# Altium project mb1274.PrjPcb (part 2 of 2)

## Sheet 05_USB_OTG_FS.SchDoc: USB_OTG_FS
size A4; Date: 04/02/2015; Author: P.A.; CompanyName: STMicroelectronics; Organization: Microcontrollers Division; Address1: 12, Rue Jules HOROWITZ; Address2: 38019 Grenoble; Address3: FRANCE; DocumentNumber: 8; Revision: E-01; SheetNumber: 8; SheetTotal: 12; Project: STM32F413H-DISCO

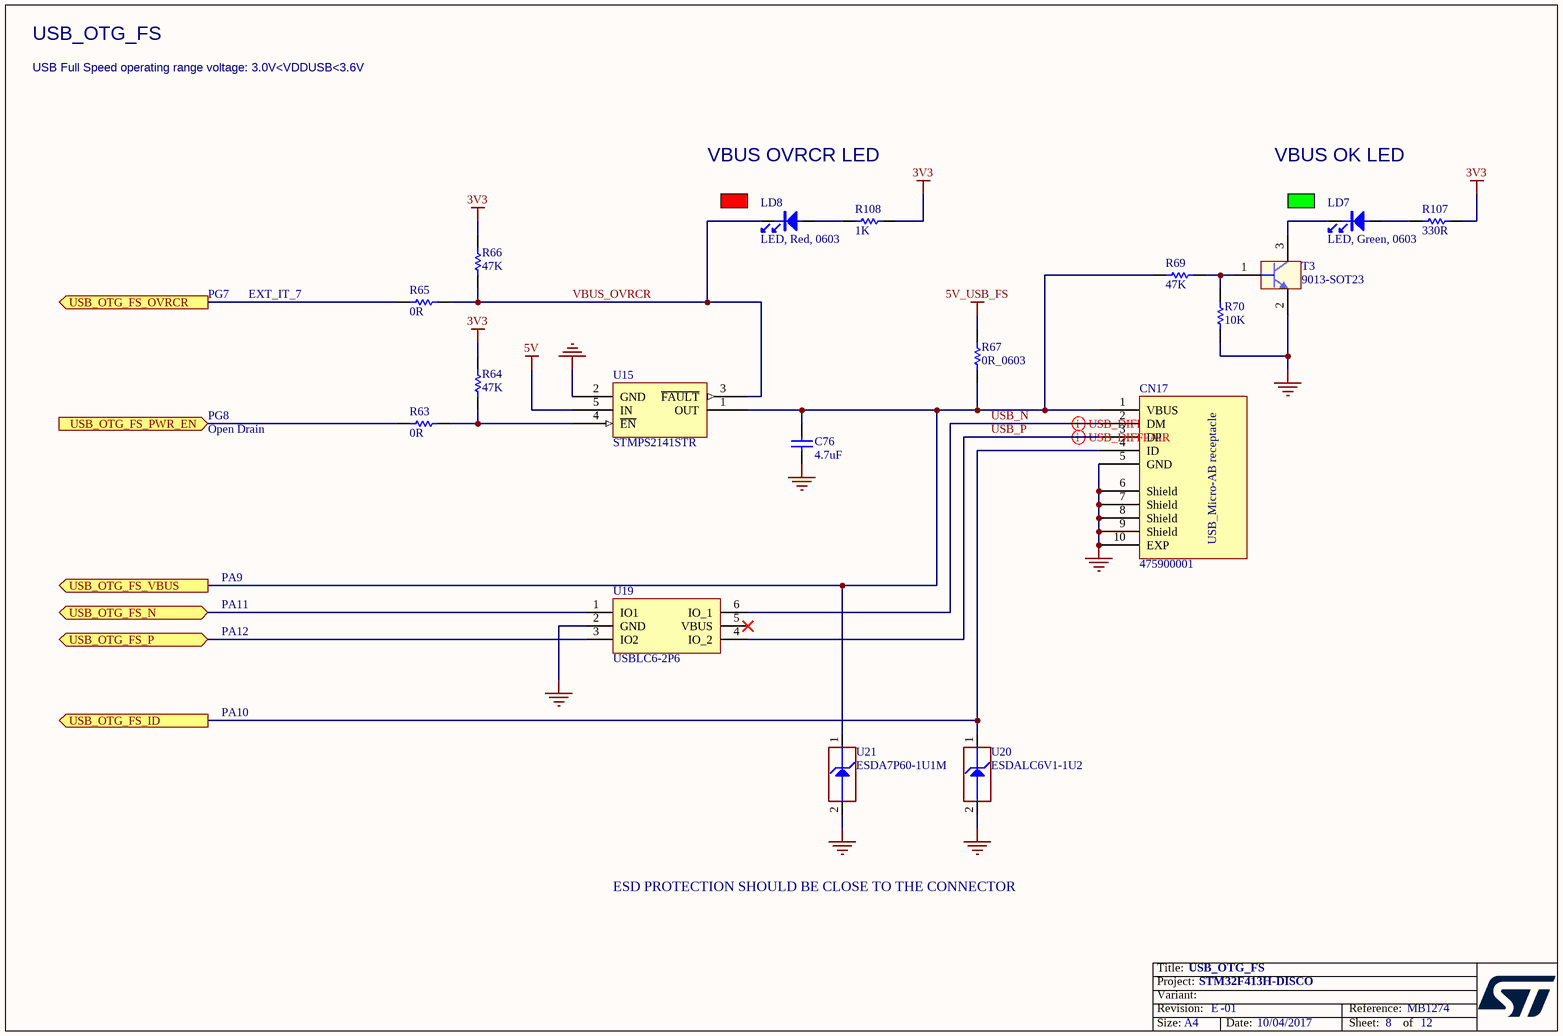
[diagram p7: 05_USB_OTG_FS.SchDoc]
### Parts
C76  4.7uF  [C0603]
CN17  475900001  [CON_USBMICROAB_MOLEX_47590-0001_H3]
LD7  LED, Green, 0603  [LED_0603_GREEN]
LD8  LED, Red, 0603  [LED_0603_RED]
R63  0R  [R0402]
R64  47K  [R0402]
R65  0R  [R0402]
R66  47K  [R0402]
R67  0R_0603  [R0603]
R69  47K  [R0402]
R70  10K  [R0402]
R107  330R  [R0402]
R108  1K  [R0402]
T3  9013-SOT23  [NPN_SOT23]
U15  STMPS2141STR  [MOS_SOT23-5L]
U19  USBLC6-2P6  [ESD_SOT666]
U20  ESDALC6V1-1U2  [ESD_ST0201]
U21  ESDA7P60-1U1M  [ESD_QFN2_1P6X1_P125]

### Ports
USB_OTG_FS_ID (out), USB_OTG_FS_N (bidir), USB_OTG_FS_OVRCR (out), USB_OTG_FS_P (bidir), USB_OTG_FS_PWR_EN (in), USB_OTG_FS_VBUS (out)

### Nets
3V3: R64.2 R66.2 R107.2 R108.1
5V: U15.5(IN)
5V_USB_FS: R67.2
GND: C76.1 CN17.5(GND) CN17.6(Shield) CN17.7(Shield) CN17.8(Shield) CN17.9(Shield) CN17.10(EXP) R70.1 T3.2(E) U15.2(GND) U19.2(GND) U20.2(GND) U21.2(GND)
USB_N: CN17.2(DM) U19.6(IO_1)
USB_OTG_FS_ID: CN17.4(ID) U20.1(IO1) ; port USB_OTG_FS_ID
USB_OTG_FS_N: U19.1(IO1) ; port USB_OTG_FS_N
USB_OTG_FS_OVRCR: R65.1 ; port USB_OTG_FS_OVRCR
USB_OTG_FS_P: U19.3(IO2) ; port USB_OTG_FS_P
USB_OTG_FS_PWR_EN: R63.1 ; port USB_OTG_FS_PWR_EN
USB_OTG_FS_VBUS: C76.2 CN17.1(VBUS) R67.1 R69.1 U15.1(OUT) U21.1(IO1) ; port USB_OTG_FS_VBUS
USB_P: CN17.3(DP) U19.4(IO_2)
VBUS_OVRCR: LD8.2 R65.2 R66.1 U15.3(~{FAULT})
NetLD7_1: LD7.1 R107.1
NetLD7_2: LD7.2 T3.3(C)
NetLD8_1: LD8.1 R108.2
NetR63_2: R63.2 R64.1 U15.4(~{EN})
NetR69_2: R69.2 R70.2 T3.1(B)

Not connected (* = marked no-connect by the designer): U19 5(VBUS)*

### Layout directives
differential pair; rule Matched Net Lengths [Tolerance = 0.5mm]; rule Impedance Constraint [Min = 85.00    Max = 95.00    ]: USB_N, USB_P

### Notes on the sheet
- USB_OTG_FS
- USB Full Speed operating range voltage: 3.0V<VDDUSB<3.6V
- VBUS OVRCR LED
- VBUS OK LED
- PG7
- EXT_IT_7
- Open Drain
- PG8
- PA9
- PA11
- PA12
- PA10
- ESD PROTECTION SHOULD BE CLOSE TO THE CONNECTOR

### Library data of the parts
C76 = Cap_4.7uF_X5R_10%_0603: Capacitor,4.7uF,16V, X5R,10%,0603,YAGEO; Manuf_Part_1: CC0603KRX5R7BB475; Fitted: YES; Order_Code: CC0603KRX5R7BB105; Ordered_By: subcon
CN17 = 475900001: USB-MICRO-AB, 47590-0001, SMT, MOLEX; Fitted: YES; Ordered_By: Subcon
LD7 = LED_green: Manuf_1: everlight; Manuf_Part_1: 19-213SYGC/S530-E2/TR8; ECCN_US/EU: EAR99/NEC; Fitted: YES; Ordered_By: Subcon
LD8 = LED_red: Manuf_1: everlight; Manuf_Part_1: 19-213-R6C-AP1Q2B/3T; ECCN_US/EU: EAR99/NEC; Fitted: YES; Ordered_By: Subcon
R63 R65 = Res_0_5%_0402: Resistor,0R,0402,5%,YAGEO; Manuf_Part_1: RC0402JR-070RL; Fitted: YES; Order_Code: 2363467; Ordered_By: Subcon
R64 R66 R69 = Res_47K_1%_0402: Resistor,47K,0402,1%,YAGEO; Manuf_Part_1: RC0402FR-0747KL; Fitted: YES; Order_Code: 9239430; Ordered_By: Subcon
R67 = Res_0_5%_0603: Resistor,0R,0603,5%,YAGEO; Manuf_Part_1: RC0603JR-070RL; Fitted: YES; Order_Code: 2363481; Ordered_By: subcon
R70 = Res_10K_1%_0402: Resistor,10K,0402,1%,YAGEO; Manuf_Part_1: RC0402FR-0710KL; Fitted: YES; Ordered_By: subcon
R107 = Res_330_1%_0402: Resistor,330R,0402,1%,YAGEO; Manuf_Part_1: RC0402FR-07330RL; Fitted: YES; Ordered_By: Subcon
R108 = Res_1K_1%_0402: Resistor,1K,0402,1%,YAGEO; Manuf_Part_1: RC0402FR-071KL; Fitted: YES; Ordered_By: Subcon
T3 = 9013-SOT23: NPN Bipolar Transistor; Manuf_1: NXP; Manuf_Part_1: BSR14; ECCN_US/EU: EAR99/NEC; Fitted: YES; Order_Code: 1081310; Ordered_By: Subcon
U15 = STMPS2141STR: Enhanced single channel power switches; Manuf_1: STM; ECCN_US/EU: EAR99/NEC; Ref St: 9159003; Fitted: YES
U19 = USBLC6-2P6: USB ESD protection; Ordered_By: STM; ECCN_US/EU: EAR99; Fitted: YES
U20 = ESDALC6V1-1U2: Dual Transil array for ESD protection; Manuf_1: STM; Ref St: .; ECCN_US/EU: EAR99/NEC; Fitted: YES; Provided: ST
U21 = MCD-00251: High power transient voltage suppressor, 7V breakdown; Manuf_1: STM; ECCN_US/EU: EAR99/NEC; Fitted: YES

## Sheet 06_Peripherals.SchDoc: Peripherals
size A4; Date: 9/24/2014; Author: P.A.; CompanyName: STMicroelectronics; Organization: Microcontrollers Division; Address1: 12, Rue Jules HOROWITZ; Address2: 38019 Grenoble; Address3: FRANCE; DocumentNumber: 9; Revision: E-01; SheetNumber: 9; SheetTotal: 12; Project: STM32F413H-DISCO

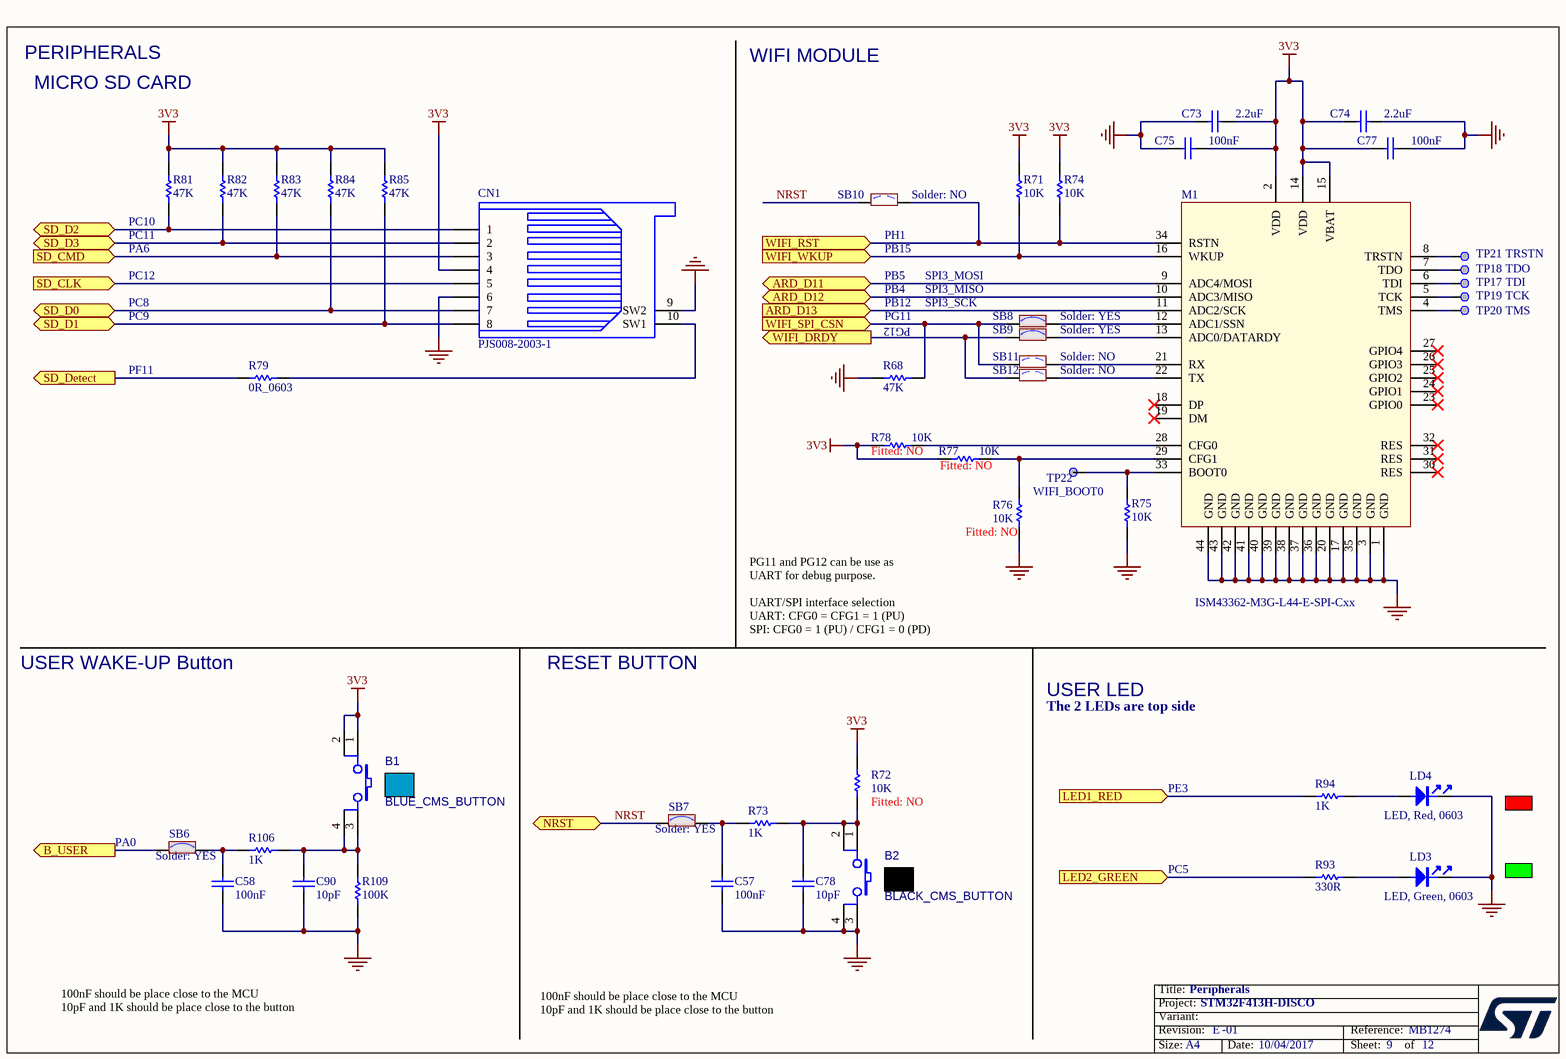
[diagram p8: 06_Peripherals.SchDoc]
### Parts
B1  BLUE_CMS_BUTTON  [SWI_C&K_KSC721GLFS_BLUE]
B2  BLACK_CMS_BUTTON  [SWI_C&K_KSC321GLFS_BLACK]
C57  100nF  [C0402]
C58  100nF  [C0402]
C73  2.2uF  [C0603]
C74  2.2uF  [C0603]
C75  100nF  [C0402]
C77  100nF  [C0402]
C78  10pF  [C0402]
C90  10pF  [C0402]
CN1  PJS008-2003-1  [CON_MICROSD_YAMAICHI_PJS008-2003-1]
LD3  LED, Green, 0603  [LED_0603_GREEN]
LD4  LED, Red, 0603  [LED_0603_RED]
M1  ISM43362-M3G-L44-E-SPI-Cxx  [MOD_WIFI_INVENTEK-SYSTEMS_ISM43362-M3G-L44-E-SPI-CXX]
R68  47K  [R0402]
R71  10K  [R0402]
R72  10K  Fitted: NO  [R0402]
R73  1K  [R0402]
R74  10K  [R0402]
R75  10K  [R0402]
R76  10K  Fitted: NO  [R0402]
R77  10K  Fitted: NO  [R0402]
R78  10K  Fitted: NO  [R0402]
R79  0R_0603  [R0603]
R81  47K  [R0402]
R82  47K  [R0402]
R83  47K  [R0402]
R84  47K  [R0402]
R85  47K  [R0402]
R93  330R  [R0402]
R94  1K  [R0402]
R106  1K  [R0402]
R109  100K  [R0402]
SB6  Solder: YES  [SOLDER-BRIDGE_R0603-0R]  (hidden comment: SB_ON)
SB7  Solder: YES  [SOLDER-BRIDGE_R0603-0R]  (hidden comment: SB_ON)
SB8  Solder: YES  [SOLDER-BRIDGE_R0603-0R]  (hidden comment: SB_ON)
SB9  Solder: YES  [SOLDER-BRIDGE_R0603-0R]  (hidden comment: SB_ON)
SB10  Solder: NO  [SOLDER-BRIDGE_R0603-0R]  (hidden comment: SB_OFF)
SB11  Solder: NO  [SOLDER-BRIDGE_R0603-0R]  (hidden comment: SB_OFF)
SB12  Solder: NO  [SOLDER-BRIDGE_R0603-0R]  (hidden comment: SB_OFF)
TP17  TDI  [TP_SMD_2MM]
TP18  TDO  [TP_SMD_2MM]
TP19  TCK  [TP_SMD_2MM]
TP20  TMS  [TP_SMD_2MM]
TP21  TRSTN  [TP_SMD_2MM]
TP22  WIFI_BOOT0  [TP_SMD_1MM]

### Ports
ARD_D11 (bidir), ARD_D12 (bidir), ARD_D13 (in), B_USER (out), LED1_RED (in), LED2_GREEN (in), NRST (bidir), SD_CLK (in), SD_CMD (in), SD_D0 (bidir), SD_D1 (bidir), SD_D2 (bidir), SD_D3 (bidir), SD_Detect (out), WIFI_DRDY (out), WIFI_RST (in), WIFI_SPI_CSN (in), WIFI_WKUP (in)

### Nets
3V3: B1.1 B1.2 C73.1 C74.1 C75.2 C77.1 CN1.4 M1.2(VDD) M1.14(VDD) M1.15(VBAT) R71.2 R72.2 R74.2 R77.1 R78.1 R81.2 R82.2 R83.2 R84.2 R85.2
GND: B2.3 B2.4 C57.1 C58.1 C73.2 C74.2 C75.1 C77.2 C78.1 C90.1 CN1.6 CN1.9(SW2) LD3.2 LD4.2 M1.1(GND) M1.3(GND) M1.17(GND) M1.20(GND) M1.35(GND) M1.36(GND) M1.37(GND) M1.38(GND) M1.39(GND) M1.40(GND) M1.41(GND) M1.42(GND) M1.43(GND) M1.44(GND) R68.1 R75.2 R76.2 R109.1
ARD_D11: M1.9(ADC4/MOSI) ; port ARD_D11
ARD_D12: M1.10(ADC3/MISO) ; port ARD_D12
ARD_D13: M1.11(ADC2/SCK) ; port ARD_D13
B_USER: SB6.1 ; port B_USER
LED1_RED: R94.2 ; port LED1_RED
LED2_GREEN: R93.1 ; port LED2_GREEN
NRST: SB7.1 SB10.1 ; port NRST
SD_CLK: CN1.5 ; port SD_CLK
SD_CMD: CN1.3 R83.1 ; port SD_CMD
SD_D0: CN1.7 R84.1 ; port SD_D0
SD_D1: CN1.8 R85.1 ; port SD_D1
SD_D2: CN1.1 R81.1 ; port SD_D2
SD_D3: CN1.2 R82.1 ; port SD_D3
SD_Detect: R79.1 ; port SD_Detect
WIFI_DRDY: SB9.1 SB12.1 ; port WIFI_DRDY
WIFI_RST: M1.34(RSTN) R74.1 SB10.2 ; port WIFI_RST
WIFI_SPI_CSN: R68.2 SB8.1 SB11.1 ; port WIFI_SPI_CSN
WIFI_WKUP: M1.16(WKUP) R71.1 ; port WIFI_WKUP
NetB1_3: B1.3 B1.4 C90.2 R106.2 R109.2
NetB2_1: B2.1 B2.2 C78.2 R72.1 R73.2
NetC57_2: C57.2 R73.1 SB7.2
NetC58_2: C58.2 R106.1 SB6.2
NetCN1_10: CN1.10(SW1) R79.2
NetLD3_1: LD3.1 R93.2
NetLD4_1: LD4.1 R94.1
NetM1_4: M1.4(TMS) TP20.1
NetM1_5: M1.5(TCK) TP19.1
NetM1_6: M1.6(TDI) TP17.1
NetM1_7: M1.7(TDO) TP18.1
NetM1_8: M1.8(TRSTN) TP21.1
NetM1_12: M1.12(ADC1/SSN) SB8.2
NetM1_13: M1.13(ADC0/DATARDY) SB9.2
NetM1_21: M1.21(RX) SB11.2
NetM1_22: M1.22(TX) SB12.2
NetM1_28: M1.28(CFG0) R78.2
NetM1_29: M1.29(CFG1) R76.1 R77.2
NetM1_33: M1.33(BOOT0) R75.1 TP22.1

Not connected (* = marked no-connect by the designer): M1 18(DP)* 19(DM)* 23(GPIO0)* 24(GPIO1)* 25(GPIO2)* 26(GPIO3)* 27(GPIO4)* 30(RES)* 31(RES)* 32(RES)*

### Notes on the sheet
- PERIPHERALS
- WIFI MODULE
- MICRO SD CARD
- (near R81) PC10
- (near R81) PC11
- (near R81) PA6
- (near SB10) PB15
- (near SB10) PH1
- PC12
- PC8
- PC9
- PG11
- PB5
- PB4
- PB12
- (near R68) PG12
- SPI3_MOSI
- SPI3_SCK
- SPI3_MISO
- PF11
- PG11 and PG12 can be use as UART for debug purpose.
- USER WAKE-UP Button
- RESET BUTTON
- UART/SPI interface selection
  UART: CFG0 = CFG1 = 1 (PU)
  SPI: CFG0 = 1 (PU) / CFG1 = 0 (PD)
- The 2 LEDs are top side
- USER LED
- PE3
- (near SB6) PA0
- PC5
- 100nF should be place close to the MCU
  10pF and 1K should be place close to the button

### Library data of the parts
B1 = Tactile_switch_CMS_BLUE_2.25N: Manuf_1: C&K; Manuf_Part_1: KSC721GLFS; Ref St: .; Ordered_By: Subcon; Fitted: YES
B2 = Tactile_switch_CMS_BLACK_2N: Manuf_1: C&K; Manuf_Part_1: KSC321GLFS; Ref St: .; Ordered_By: Subcon; Fitted: YES
C57 C58 C75 C77 = Cap_100nF_X7R_10%_0402: Capacitor,100nF,16V,X7R,10%,0402,YAGEO; Manuf_Part_1: CC0402KRX7R7BB104; Fitted: YES; Ordered_By: Subcon
C73 C74 = Cap_2.2uF_X5R_10%_0603: Capacitor,2.2uF,10V, X5R,10%,0603,YAGEO; Manuf_Part_1: CC0603KRX5R6BB225; Manuf_Part_2: C0603C225K8PACTU; Manuf_2: KEMET; Fitted: YES; Ordered_By: Subcon
C78 C90 = Cap_10pF_NPO_5%_0402: Capacitor,10pF,50V,NPO,5%,0402,YAGEO; Manuf_Part_1: CC0402JRNPO9BN100; Fitted: YES; Ordered_By: subcon
CN1 = microSD-PJS008-2003: Memory Card Connectors MicroSD Card Conn Revrs Mnt Push-Push; Manuf_1: YAMAICHI; Fitted: YES; Ordered_By: Subcon
LD3 = LED_green: as LD7 on sheet 05_USB_OTG_FS
LD4 = LED_red: as LD8 on sheet 05_USB_OTG_FS
M1 = ISM43362-M3G-L44-E: WIFI Module ISM43362-M3G-L44-E: IEEE802.11 b/g/n integrated Antenna; Manuf_1: Inventek; ECCN_US/EU: EAR99; Ordered_By: Subcon; Fitted: YES
R68 = Res_47K_1%_0402: Resistor,47K,0402,1%,YAGEO; Manuf_Part_1: RC0402FR-0747KL; Order_Code: 9239430; Fitted: YES; Ordered_By: Subcon
R71 R74 R75 = Res_10K_1%_0402: as R70 on sheet 05_USB_OTG_FS
R72 R76-R78 = Res_10K_1%_0402: Resistor,10K,0402,1%,YAGEO; Manuf_Part_1: RC0402FR-0710KL; Ordered_By: subcon
R73 R94 R106 = Res_1K_1%_0402: as R108 on sheet 05_USB_OTG_FS
R79 = Res_0_5%_0603: as R67 on sheet 05_USB_OTG_FS
R81-R85 = Res_47K_1%_0402: as R64 on sheet 05_USB_OTG_FS
R93 = Res_330_1%_0402: as R107 on sheet 05_USB_OTG_FS
R109 = Res_100K_1%_0402: Resistor,100K,0402,1%,YAGEO; Manuf_Part_2: RT0402FRE07100KL; Manuf_Part_1: RC0402FR-07100KL; Fitted: YES; Ordered_By: Subcon
SB6-SB9 = SB_ON: Solder Bridge ON; Ordered_by: Subcon
SB10-SB12 = SB_OFF: Solder Bridge OFF; Fitted: NO; Ordered_By: Subcon
TP17-TP21 = TP 2mm: Test Point; Fitted: YES; Ordered_By: Subcon
TP22 = TP 1mm: Test Point; Fitted: YES; Ordered_By: Subcon

## Sheet 07_Arduino_ Connectors.SchDoc: Arduino Uno connector
size A4; Date: 2/4/2015; Author: P.A.; CompanyName: STMicroelectronics; Organization: Microcontrollers Division; Address1: 12, Rue Jules HOROWITZ; Address2: 38019 Grenoble; Address3: FRANCE; DocumentNumber: 10; Revision: E-01; SheetNumber: 10; SheetTotal: 12; Project: STM32F413H-DISCO

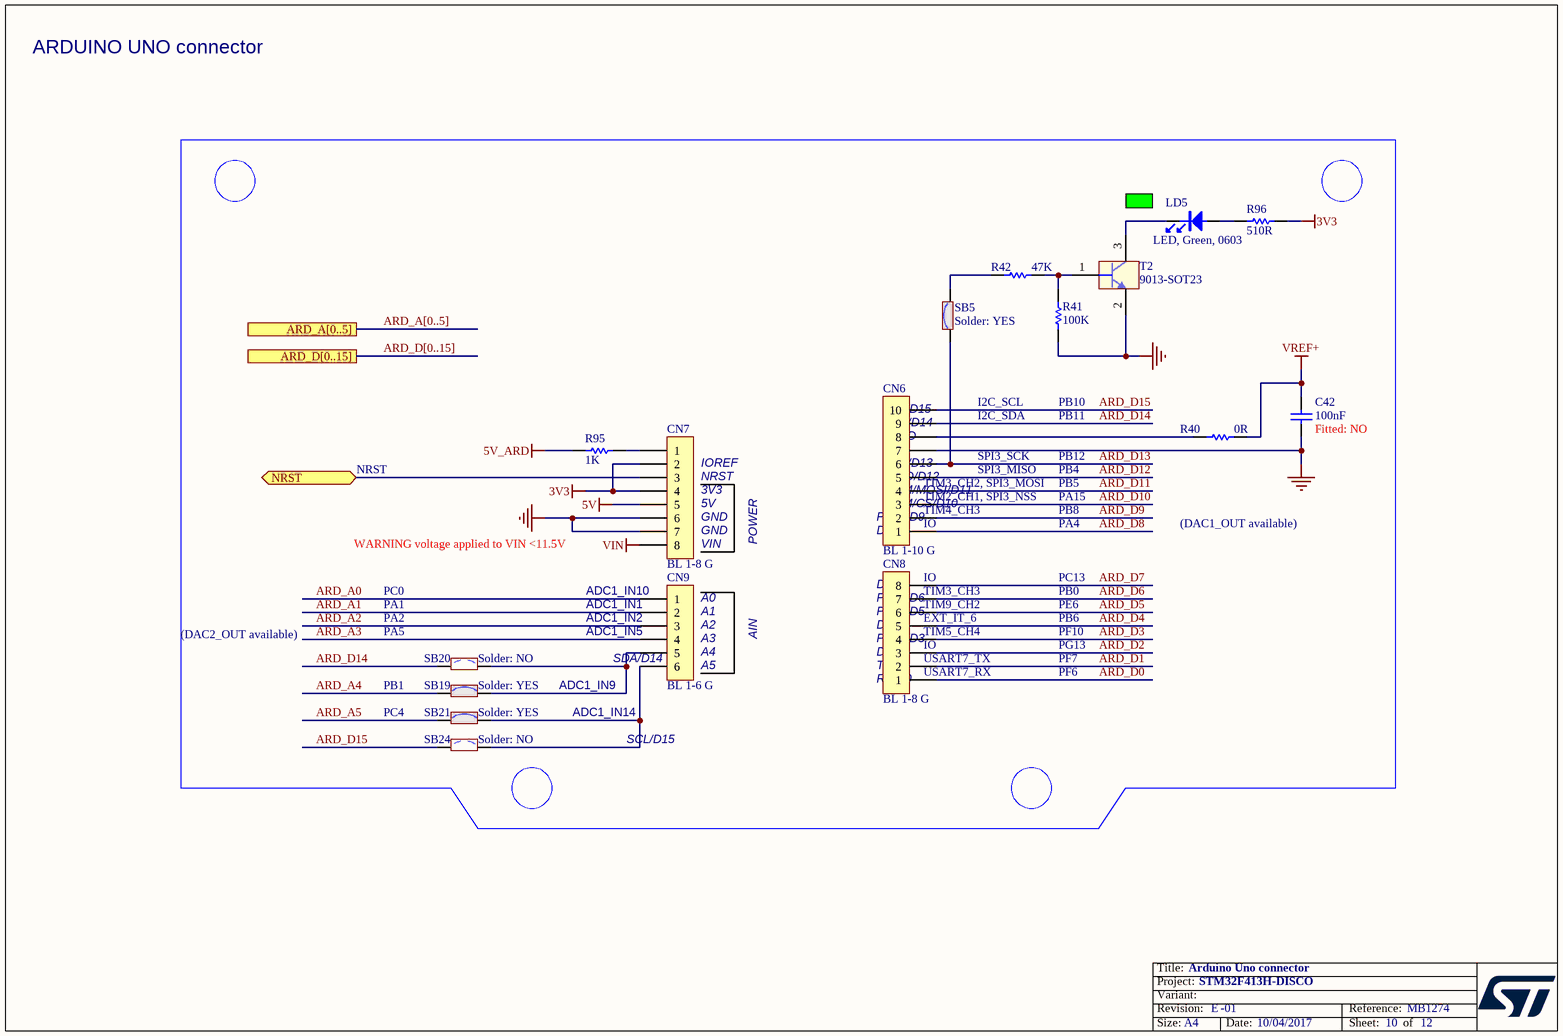
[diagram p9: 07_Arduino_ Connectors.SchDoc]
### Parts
C42  100nF  Fitted: NO  [C0402]
CN6  BL 1-10 G  [CON_FISCHER_BL1-10-G]
CN7  BL 1-8 G  [CON_FISCHER_BL1-8-G]
CN8  BL 1-8 G  [CON_FISCHER_BL1-8-G]
CN9  BL 1-6 G  [CON_FISCHER_BL1-6-G]
LD5  LED, Green, 0603  [LED_0603_GREEN]
R40  0R  [R0402]
R41  100K  [R0402]
R42  47K  [R0402]
R95  1K  [R0603]
R96  510R  [R0402]
SB5  Solder: YES  [SOLDER-BRIDGE_R0603-0R]  (hidden comment: SB_ON)
SB19  Solder: YES  [SOLDER-BRIDGE_R0603-0R]  (hidden comment: SB_ON)
SB20  Solder: NO  [SOLDER-BRIDGE_R0603-0R]  (hidden comment: SB_OFF)
SB21  Solder: YES  [SOLDER-BRIDGE_R0603-0R]  (hidden comment: SB_ON)
SB24  Solder: NO  [SOLDER-BRIDGE_R0603-0R]  (hidden comment: SB_OFF)
T2  9013-SOT23  [NPN_SOT23]

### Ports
ARD_A[0..5], ARD_D[0..15], NRST (bidir)

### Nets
3V3: CN7.2 CN7.4 R96.2
5V: CN7.5
5V_ARD: R95.1
GND: C42.1 CN6.7 CN7.6 CN7.7 R41.1 T2.2(E)
VIN: CN7.8
VREF+: C42.2 R40.2
ARD_A0: CN9.1
ARD_A1: CN9.2
ARD_A2: CN9.3
ARD_A3: CN9.4
ARD_A4: SB19.1
ARD_A5: SB21.1
ARD_D0: CN8.1
ARD_D1: CN8.2
ARD_D2: CN8.3
ARD_D3: CN8.4
ARD_D4: CN8.5
ARD_D5: CN8.6
ARD_D6: CN8.7
ARD_D7: CN8.8
ARD_D8: CN6.1
ARD_D9: CN6.2
ARD_D10: CN6.3
ARD_D11: CN6.4
ARD_D12: CN6.5
ARD_D13: CN6.6 SB5.1
ARD_D14: CN6.9 SB20.1
ARD_D15: CN6.10 SB24.1
NRST: CN7.3 ; port NRST
NetCN6_8: CN6.8 R40.1
NetCN7_1: CN7.1 R95.2
NetCN9_5: CN9.5 SB19.2 SB20.2
NetCN9_6: CN9.6 SB21.2 SB24.2
NetLD5_1: LD5.1 R96.1
NetLD5_2: LD5.2 T2.3(C)
NetR41_2: R41.2 R42.2 T2.1(B)
NetR42_1: R42.1 SB5.2

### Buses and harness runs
bus ARD_A[0..5] = port ARD_A[0..5]
bus ARD_D[0..15] = port ARD_D[0..15]

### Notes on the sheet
- ARDUINO UNO connector
- (near CN6) SDA/D14
- (near CN6) SCL/D15
- (near CN6) AVDD
- I2C_SCL
- I2C_SDA
- PB10
- PB11
- NRST
- (near CN7) IOREF
- (near CN7) NRST
- (near CN7) 3V3
- (near CN7) 5V
- (near CN7) GND
- (near CN6) PWM/D9
- (near CN6) PWM/CS/D10
- (near CN6) SCK/D13
- (near CN6) MISO/D12
- (near CN6) PWM/MOSI/D11
- (near CN6) GND
- (near CN6) TIM4_CH3
- (near CN6) TIM2_CH1, SPI3_NSS
- (near CN6) TIM3_CH2, SPI3_MOSI
- SPI3_SCK
- SPI3_MISO
- PB8
- PA15
- PB5
- PB4
- PB12
- WARNING voltage applied to VIN <11.5V
- (near CN7) VIN
- POWER
- (near CN6) D8
- (near CN8) IO
- (near CN6) IO
- PC13
- PA4
- (DAC1_OUT available)
- (DAC2_OUT available)
- PC0
- PA1
- PA2
- PA5
- (near CN9) ADC1_IN5
- (near CN9) ADC1_IN2
- (near CN9) ADC1_IN1
- (near CN9) ADC1_IN10
- (near CN9) A0
- (near CN9) A1
- (near CN9) A2
- (near CN9) A3
- (near CN9) A4
- AIN
- (near CN8) D2
- (near CN8) D4
- (near CN8) PWM/D3
- (near CN8) PWM/D5
- (near CN8) PWM/D6
- (near CN8) D7
- (near CN8) TIM5_CH4
- (near CN8) TIM9_CH2
- (near CN8) TIM3_CH3
- (near CN8) EXT_IT_6
- PG13
- PF10
- PB6
- PE6
- PB0
- PB1
- PC4
- ADC1_IN9
- ADC1_IN14
- SDA/D14
- (near CN9) A5
- (near CN8) RX/D0
- (near CN8) TX/D1
- (near CN8) USART7_RX
- (near CN8) USART7_TX
- PF6
- PF7
- SCL/D15

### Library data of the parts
C42 = Cap_100nF_X7R_10%_0402: Capacitor,100nF,16V,X7R,10%,0402,YAGEO; Manuf_Part_1: CC0402KRX7R7BB104; Ordered_By: Subcon
CN6 = Header 10X1_Female_THT: Header, 10-Pin, Single row, female, THT, 2.54; Manuf_1: Fischer Electronik; Fitted: YES; Ordered_By: Subcon
CN7 CN8 = Header 8X1_Female_THT: Header, 8-Pins, Single row, female, THT, 2.54; Manuf_1: Fischer Electronik; Fitted: YES; Ordered_By: Subcon
CN9 = Header 6X1_Female_THT: Header, 6-Pins, Single row, female THT, 2.54; Manuf_1: Fischer Electronik; Fitted: YES; Ordered_By: Subcon
LD5 = LED_green: as LD7 on sheet 05_USB_OTG_FS
R40 = Res_0_5%_0402: as R63 on sheet 05_USB_OTG_FS
R41 = Res_100K_1%_0402: Resistor,100K,0402,1%,YAGEO; Manuf_Part_1: RC0402FR-07100KL; Manuf_Part_2: RT0402FRE07100KL; Fitted: YES; Ordered_By: Subcon
R42 = Res_47K_1%_0402: as R64 on sheet 05_USB_OTG_FS
R95 = Res_1K_1%_0603: Resistor,1K,0603,1%,YAGEO; Manuf_Part_1: RC0603FR-071KL; Fitted: YES; Ordered_By: Subcon
R96 = Res_510_1%_0402: Resistor,510R,0402,1%,YAGEO; Manuf_Part_1: RC0402FR-07510L; Fitted: YES; Ordered_By: Subcon
SB5 SB19 SB21 = SB_ON: Solder Bridge ON; Ordered_by: Subcon
SB20 SB24 = SB_OFF: as SB10-SB12 on sheet 06_Peripherals
T2 = 9013-SOT23: as T3 on sheet 05_USB_OTG_FS

## Sheet 08_ST_LINK_V2-1.SCHDOC: ST-LINK/V2-1 with support of SWD only
size A4; Date: 17-03-2016; Author: A.B; CompanyName: STMicroelectronics; Organization: Microcontrollers Division; Address1: 12, Rue Jules HOROWITZ; Address2: 38019 Grenoble; Address3: FRANCE; DocumentNumber: 11; Revision: E-01; SheetNumber: 11; SheetTotal: 12; Project: STM32F413H-DISCO

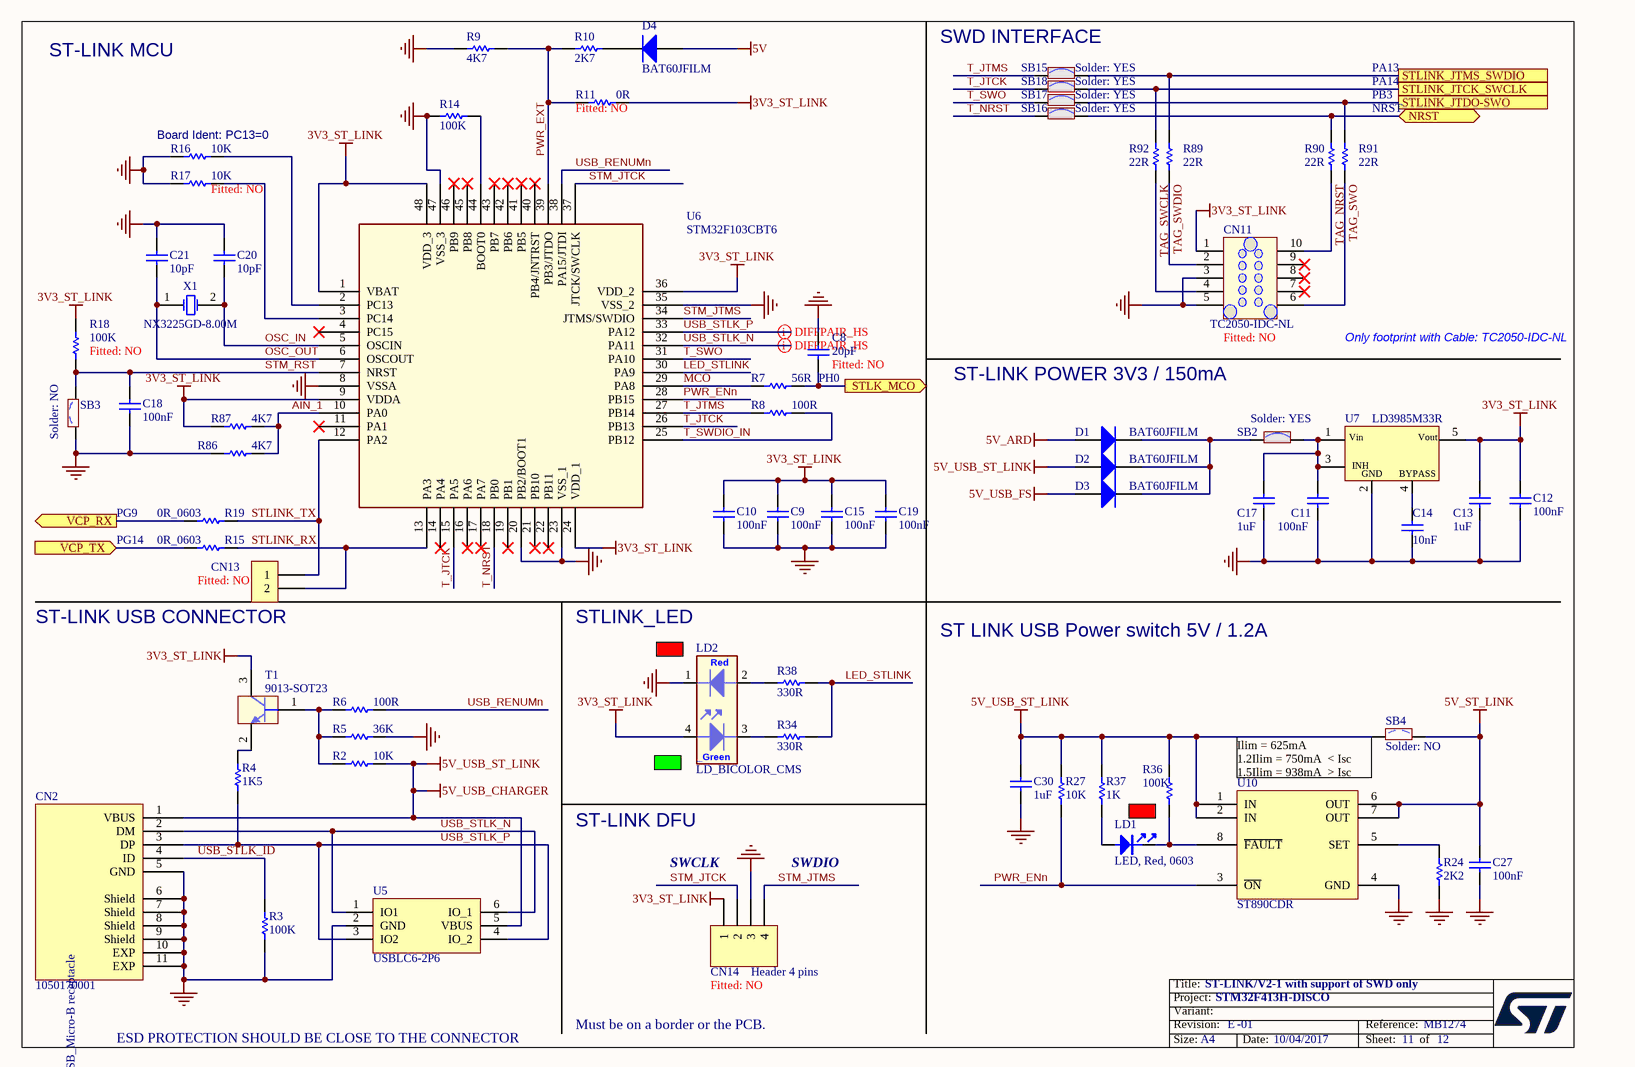
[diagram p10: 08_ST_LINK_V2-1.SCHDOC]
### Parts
C8  20pF  Fitted: NO  [C0402]
C9  100nF  [C0402]
C10  100nF  [C0402]
C11  100nF  [C0402]
C12  100nF  [C0402]
C13  1uF  [C0603]
C14  10nF  [C0603]
C15  100nF  [C0402]
C17  1uF  [C0603]
C18  100nF  [C0402]
C19  100nF  [C0402]
C20  10pF  [C0402]
C21  10pF  [C0402]
C27  100nF  [C0402]
C30  1uF  [C0603]
CN2  1050170001  [CON_USBMICROB_MOLEX_105017-0001_H2P90]
CN11  TC2050-IDC-NL  Fitted: NO  [CON_TAG-C_TC2050-IDC-NL]
CN13  Fitted: NO  [CON_SAMTEC_TSW-102-07-G-S]  (hidden comment: header 2 pins 2.54mm)
CN14  Header 4 pins  Fitted: NO  [CON_SAMTEC_TSW-104-07-G-S]
D1  BAT60JFILM  [DIO_SOD323]
D2  BAT60JFILM  [DIO_SOD323]
D3  BAT60JFILM  [DIO_SOD323]
D4  BAT60JFILM  [DIO_SOD323]
LD1  LED, Red, 0603  [LED_0603_RED]
LD2  LD_BICOLOR_CMS  [LED_BI-GR_HSMF-A201-A00J1]
R2  10K  [R0402]
R3  100K  [R0402]
R4  1K5  [R0402]
R5  36K  [R0402]
R6  100R  [R0402]
R7  56R  [R0402]
R8  100R  [R0402]
R9  4K7  [R0402]
R10  2K7  [R0402]
R11  0R  Fitted: NO  [R0402]
R14  100K  [R0402]
R15  0R_0603  [R0603]
R16  10K  [R0402]
R17  10K  Fitted: NO  [R0402]
R18  100K  Fitted: NO  [R0402]
R19  0R_0603  [R0603]
R24  2K2  [R0402]
R27  10K  [R0402]
R34  330R  [R0402]
R36  100K  [R0402]
R37  1K  [R0402]
R38  330R  [R0402]
R86  4K7  [R0402]
R87  4K7  [R0402]
R89  22R  [R0603]
R90  22R  [R0603]
R91  22R  [R0603]
R92  22R  [R0603]
SB2  Solder: YES  [SOLDER-BRIDGE_R0603-0R]  (hidden comment: SB_ON)
SB3  Solder: NO  [SOLDER-BRIDGE_R0603-0R]  (hidden comment: SB_OFF)
SB4  Solder: NO  [SOLDER-BRIDGE_R0603-0R]  (hidden comment: SB_OFF)
SB15  Solder: YES  [SOLDER-BRIDGE_R0603-0R]  (hidden comment: SB_ON)
SB16  Solder: YES  [SOLDER-BRIDGE_R0603-0R]  (hidden comment: SB_ON)
SB17  Solder: YES  [SOLDER-BRIDGE_R0603-0R]  (hidden comment: SB_ON)
SB18  Solder: YES  [SOLDER-BRIDGE_R0603-0R]  (hidden comment: SB_ON)
T1  9013-SOT23  [NPN_SOT23]
U5  USBLC6-2P6  [ESD_SOT666]
U6  STM32F103CBT6  [ICC_LQFP48_7X7_P050]
U7  LD3985M33R  [REG_SOT23-5L]
U10  ST890CDR  [ICC_SO8_5X4_P127]
X1  NX3225GD-8.00M  [CRY_NX3225GD_2P]

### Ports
NRST (bidir), STLINK_JTCK_SWCLK, STLINK_JTDO-SWO, STLINK_JTMS_SWDIO, STLK_MCO (out), VCP_RX (out), VCP_TX (in)

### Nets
3V3_ST_LINK: C9.2 C10.2 C12.2 C13.2 C15.2 C19.2 CN11.1 CN14.1 LD2.4 R11.2 R18.2 R87.1 T1.3(C) U6.1(VBAT) U6.9(VDDA) U6.24(VDD_1) U6.36(VDD_2) U6.48(VDD_3) U7.5(Vout)
5V: D4.1(A)
5V_ARD: D1.1(A)
5V_ST_LINK: C27.2 SB4.2 U10.6(OUT) U10.7(OUT)
5V_USB_CHARGER: C30.2 CN2.1(VBUS) D2.1(A) R2.1 R27.2 R36.2 R37.2 SB4.1 U5.5(VBUS) U10.1(IN) U10.2(IN)  [also labelled 5V_USB_ST_LINK]
5V_USB_FS: D3.1(A)
GND: C8.1 C9.1 C10.1 C11.1 C12.1 C13.1 C14.1 C15.1 C17.1 C18.1 C19.1 C20.2 C21.2 C27.1 C30.1 CN2.5(GND) CN2.6(Shield) CN2.7(Shield) CN2.8(Shield) CN2.9(Shield) CN2.10(EXP) CN2.11(EXP) CN11.3 CN11.5 CN14.3 LD2.1 R3.1 R5.1 R9.1 R14.1 R16.2 R17.2 R24.1 R86.1 SB3.1 U5.2(GND) U6.8(VSSA) U6.20(PB2/BOOT1) U6.23(VSS_1) U6.35(VSS_2) U6.47(VSS_3) U7.2(GND) U10.4(GND)
AIN_1: R86.2 R87.2 U6.10(PA0)
LED_STLINK: R34.2 R38.2 U6.30(PA9)
MCO: R7.1 U6.29(PA8)
NRST: R90.2 SB16.2 ; port NRST
OSC_IN: C20.1 U6.5(OSCIN) X1.2(OSC2)
OSC_OUT: C21.1 U6.6(OSCOUT) X1.1(OSC1)
PWR_ENn: R27.1 U6.28(PB15) U10.3(~{ON})
PWR_EXT: R9.2 R10.1 R11.1 U6.39(PB3/JTDO)
STLINK_JTCK_SWCLK: R92.2 SB18.2 ; port STLINK_JTCK_SWCLK
STLINK_JTDO-SWO: R91.2 SB17.2 ; port STLINK_JTDO-SWO
STLINK_JTMS_SWDIO: R89.2 SB15.2 ; port STLINK_JTMS_SWDIO
STLINK_RX: CN13.2 R15.2 U6.13(PA3)
STLINK_TX: CN13.1 R19.2 U6.12(PA2)
STLK_MCO: C8.2 R7.2 ; port STLK_MCO
STM_JTCK: CN14.2 U6.37(JTCK/SWCLK)
STM_JTMS: CN14.4 U6.34(JTMS/SWDIO)
STM_RST: C18.2 R18.1 SB3.2 U6.7(NRST)
T_JTCK: SB18.1 U6.15(PA5) U6.26(PB13)
T_JTMS: R8.1 SB15.1 U6.27(PB14)
T_NRST: SB16.1 U6.18(PB0)
T_SWDIO_IN: R8.2 U6.25(PB12)
T_SWO: SB17.1 U6.31(PA10)
TAG_NRST: CN11.10 R90.1
TAG_SWCLK: CN11.4 R92.1
TAG_SWDIO: CN11.2 R89.1
TAG_SWO: CN11.6 R91.1
USB_RENUMn: R6.2 U6.38(PA15/JTDI)
USB_STLK_ID: CN2.4(ID) R3.2
USB_STLK_N: CN2.2(DM) U5.1(IO1) U5.6(IO_1) U6.32(PA11)
USB_STLK_P: CN2.3(DP) R4.1 U5.3(IO2) U5.4(IO_2) U6.33(PA12)
VCP_RX: R19.1 ; port VCP_RX
VCP_TX: R15.1 ; port VCP_TX
NetC11_2: C11.2 C17.2 SB2.2 U7.1(Vin) U7.3(CE)
NetC14_2: C14.2 U7.4(BYPASS)
NetD1_2: D1.2(K) D2.2(K) D3.2(K) SB2.1
NetD4_2: D4.2(K) R10.2
NetLD1_1: LD1.1 R37.1
NetLD1_2: LD1.2 R36.1 U10.8(~{FAULT})
NetLD2_2: LD2.2 R38.1
NetLD2_3: LD2.3 R34.1
NetR2_2: R2.2 R5.2 R6.1 T1.1(B)
NetR4_2: R4.2 T1.2(E)
NetR14_2: R14.2 U6.44(BOOT0)
NetR16_1: R16.1 U6.2(PC13)
NetR17_1: R17.1 U6.3(PC14)
NetR24_2: R24.2 U10.5(SET)

Not connected (* = marked no-connect by the designer): CN11 7* 8* 9*; U6 4(PC15)* 11(PA1)* 14(PA4)* 16(PA6)* 17(PA7)* 19(PB1)* 21(PB10)* 22(PB11)* 40(PB4/JNTRST)* 41(PB5)* 42(PB6)* 43(PB7)* 45(PB8)* 46(PB9)*

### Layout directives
differential pair: USB_STLK_N, USB_STLK_P

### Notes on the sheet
- ST-LINK MCU
- SWD INTERFACE
- PA14
- PA13
- PB3
- NRST
- (near R16) Board Ident: PC13=0
- (near C8) PH0
- ST-LINK POWER 3V3 / 150mA
- Only footprint with Cable: TC2050-IDC-NL
- PG9
- PG14
- ST-LINK USB CONNECTOR
- STLINK_LED
- ST LINK USB Power switch 5V / 1.2A
- (near SB4) Ilim = 625mA
  1.2Ilim = 750mA  < Isc
  1.5Ilim = 938mA  > Isc
- ST-LINK DFU
- SWCLK
- SWDIO
- ESD PROTECTION SHOULD BE CLOSE TO THE CONNECTOR
- Must be on a border or the PCB.

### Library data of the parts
C8 = Cap_20pF_NPO_5%_0402: Capacitor,20pF,50V,NPO,5%,0402,YAGEO; Manuf_Part_1: CC0402JRNPO9BN200; Ordered_By: Subcon
C9-C12 C15 C18 C19 C27 = Cap_100nF_X7R_10%_0402: as C57 on sheet 06_Peripherals
C13 C17 C30 = Cap_1uF_X5R_10%_0603: Capacitor,1uF,16V,X5R,10%,0603,YAGEO; Manuf_Part_1: CC0603KRX5R7BB105; Fitted: YES; Ordered_By: Subcon
C14 = Cap_10nF_X7R_10%_0603: Capacitor,10nF,50V,X7R,10%,0603,YAGEO; Manuf_Part_1: CC0603KRX7R9BB103; Fitted: YES; Ordered_By: Subcon
C20 C21 = Cap_10pF_NPO_5%_0402: as C78 on sheet 06_Peripherals
CN2 = 1050170001: USB-MICRO-B, 1050170001, SMT, MOLEX; Fitted: YES; Ordered_By: Subcon
CN11 = Tag-10-C: Tag_Connector Header, 10-Pin, Dual row No legs; Manuf_Part_1: TC2050-IDC-NL-FP; Ordered_By: Subcon
CN13 = Header 2 pins: Manuf_1: SAMTEC; Manuf_Part_2: 4711955140470; Manuf_2: KONTEC; Manuf_Part_1: TSW-102-07-x-S; Order_Code: 423-2841; Ordered_By: Subcon
CN14 = Header 4: Header, 4-Pin; Manuf_1: SAMTEC; Manuf_Part_1: TSW-104-07-x-S; Ordered_By: Subcon
D1-D4 = BAT60JFILM: Manuf_1: STM; ECCN_US/EU: EAR99/NEC; Ref St: 9151097; Fitted: YES
LD1 = LED_red: as LD8 on sheet 05_USB_OTG_FS
LD2 = LD_BICOLOR_CMS: Bicolor Led; Manuf_Part_1: HSMF-A201-A00J1; Manuf_1: Avago Technologies; Manuf_2: everluck; Manuf_Part_2: LE-RGW35280; ECCN_US/EU: EAR99/NEC; Fitted: YES; Ordered_By: Subcon
R2 R16 R27 = Res_10K_1%_0402: as R70 on sheet 05_USB_OTG_FS
R3 R36 = Res_100K_1%_0402: as R109 on sheet 06_Peripherals
R4 = Res_1K5_1%_0402: Resistor,1K5,0402,1%,YAGEO; Manuf_Part_1: RC0402FR-071K5L; Fitted: YES; Ordered_By: Subcon
R5 = Res_36K_1%_0402: Resistor,36K,0402,1%,YAGEO; Manuf_Part_1: RC0402FR-0736KL; Fitted: YES; Ordered_By: Subcon
R6 R8 = Res_100_1%_0402: Resistor,100R,0402,1%,YAGEO; Manuf_Part_1: RC0402FR-07100RL; Fitted: YES; Order_Code: 9239111; Ordered_By: Subcon
R7 = Res_56_1%_0402: Resistor,56R,0402,1%,YAGEO; Manuf_Part_1: RC0402FR-0756RL; Fitted: YES; Order_Code: 9239081RL; Ordered_By: Subcon
R9 = Res_4K7_1%_0402: Resistor,4K7,0402,1%,YAGEO; Manuf_Part_1: RC0402FR-074K7L; Manuf_Part_2: RT0402FRE074K7L; Fitted: YES; Ordered_By: Subcon
R10 = Res_2K7_1%_0402: Resistor,2K7,0402,1%,YAGEO; Manuf_Part_1: RC0402FR-072K7L; Fitted: YES; Ordered_By: Subcon
R11 = Res_0_5%_0402: Resistor,0R,0402,5%,YAGEO; Manuf_Part_1: RC0402JR-070RL; Order_Code: 2363467; Ordered_By: Subcon
R14 = Res_100K_1%_0402: as R41 on sheet 07_Arduino_ Connectors
R15 R19 = Res_0_5%_0603: as R67 on sheet 05_USB_OTG_FS
R17 = Res_10K_1%_0402: as R72 on sheet 06_Peripherals
R18 = Res_100K_1%_0402: Resistor,100K,0402,1%,YAGEO; Manuf_Part_1: RC0402FR-07100KL; Manuf_Part_2: RT0402FRE07100KL; Ordered_By: Subcon
R24 = Res_2K2_1%_0402: Resistor,2K2,0402,1%,YAGEO; Manuf_Part_1: RC0402FR-072K2L; Fitted: YES; Ordered_By: Subcon
R34 R38 = Res_330_1%_0402: as R107 on sheet 05_USB_OTG_FS
R37 = Res_1K_1%_0402: as R108 on sheet 05_USB_OTG_FS
R86 R87 = Res_4K7_1%_0402: Resistor,4K7,0402,1%,YAGEO; Manuf_Part_2: RT0402FRE074K7L; Manuf_Part_1: RC0402FR-074K7L; Fitted: YES; Ordered_By: Subcon
R89-R92 = Res_22_1%_0603: Resistor,22R,0603,1%,Yageo; Manuf_Part_1: RC0603FR-0722RL; Fitted: YES; Ordered_By: Subcon
SB2 SB15-SB18 = SB_ON: Solder Bridge ON; Ordered_by: Subcon
SB3 SB4 = SB_OFF: as SB10-SB12 on sheet 06_Peripherals
T1 = 9013-SOT23: as T3 on sheet 05_USB_OTG_FS
U5 = USBLC6-2P6: as U19 on sheet 05_USB_OTG_FS
U6 = STM32F103CBT6: Medium-density performance line ARM-based 32-bit MCU with 128KB Flash; Manuf_1: STM; ECCN_US/EU: 3A991A2/NEC; Fitted: YES
U7 = LD3985M33R: Ultra low drop-low noise BiCMOS voltage, regulators low ESR capacitors compatible; Manuf_1: STM; Ref St: 9176161; ECCN_US/EU: EAR99/NEC; Fitted: YES
U10 = ST890CDR: 1.2 A current limited high-side power switch with thermal shutdown; Manuf_1: STM; ECCN_US/EU: EAR99/NEC; Fitted: YES
X1 = XTAL_8M_NX3225GD: Crystal 8Mhz, 8pF, -+50PPM, SMD; Manuf_1: NDK; Manuf_Part_1: NX3225GD 8MHz EXS00A-CG04874; ECCN_US/EU: EAR99/NEC; NDK Ref: X3127326; Ref St: 9157029; Fitted: YES; Ordered_By: STM

## Sheet 09_Power.SchDoc: Power
size A4; Date: 9/24/2014; Author: P.A.; CompanyName: STMicroelectronics; Organization: Microcontrollers Division; Address1: 12, Rue Jules HOROWITZ; Address2: 38019 Grenoble; Address3: FRANCE; DocumentNumber: 12; Revision: E-01; SheetNumber: 12; SheetTotal: 12; Project: STM32F413H-DISCO

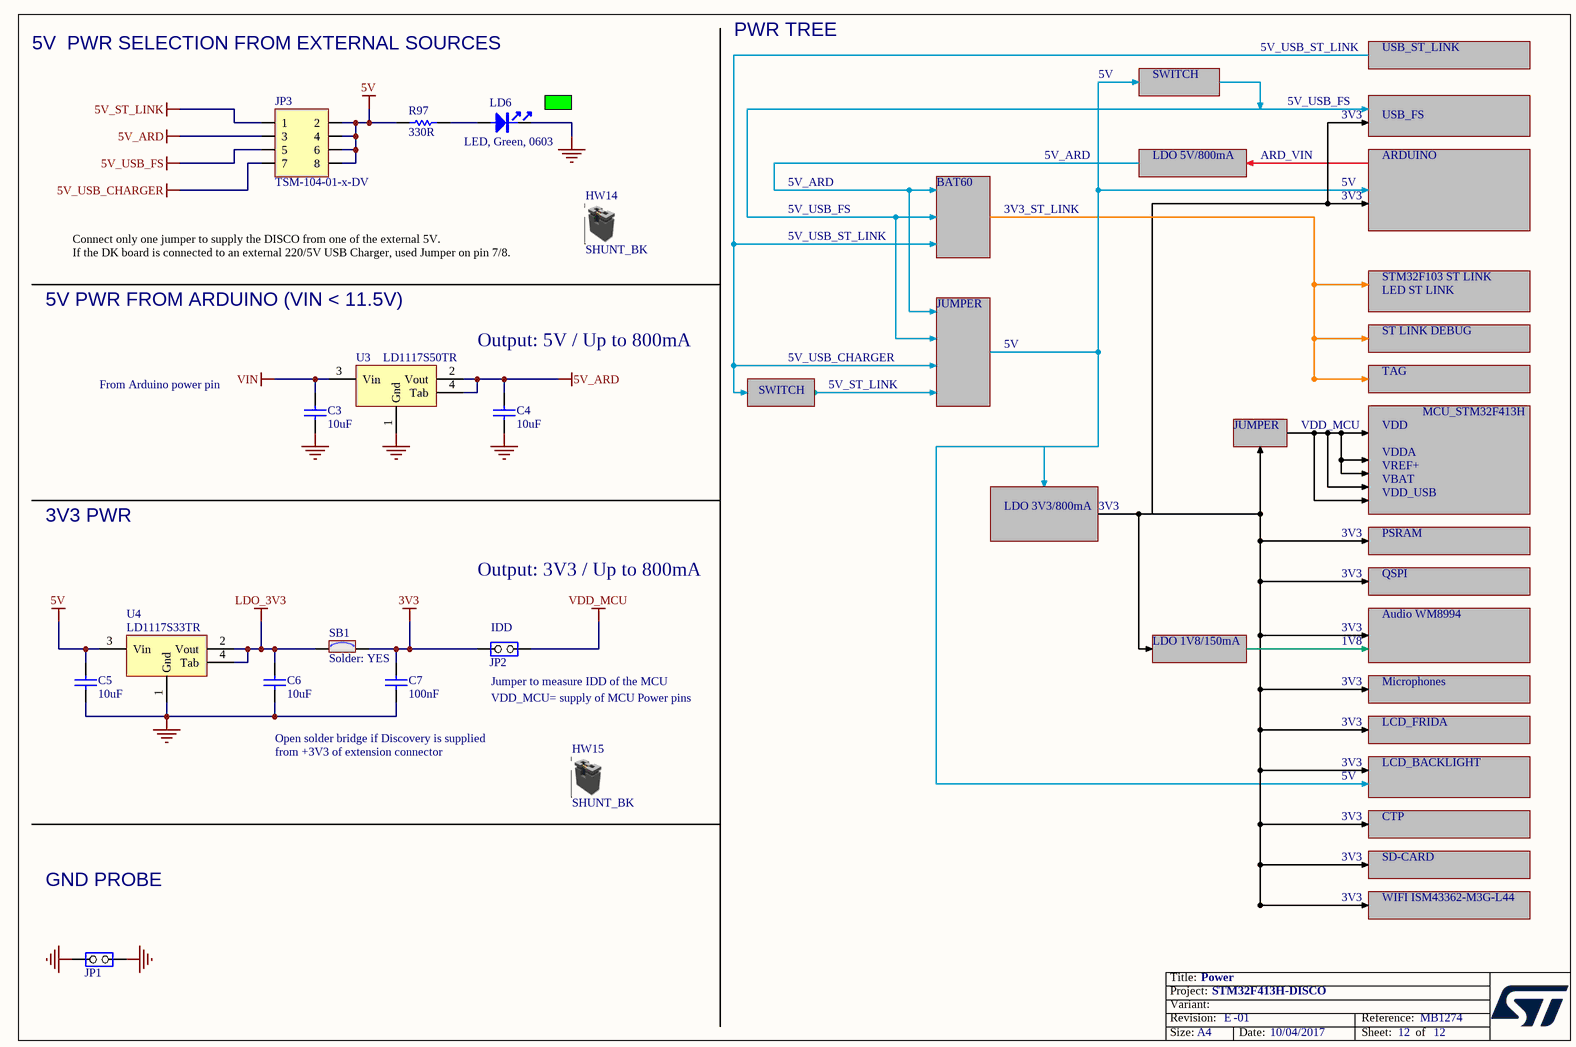
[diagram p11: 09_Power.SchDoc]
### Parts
C3  10uF  [C0805]
C4  10uF  [C0805]
C5  10uF  [C0805]
C6  10uF  [C0805]
C7  100nF  [C0402]
HW14  SHUNT_BK  (mechanical)
HW15  SHUNT_BK  (mechanical)
JP1  Jumper_2.54mm  [CON_SAMTEC_TSW-102-07-G-S]  (value not drawn)
JP2  Jumper_2.54mm  [CON_SAMTEC_TSW-102-07-G-S]  (value not drawn)
JP3  TSM-104-01-x-DV  [CON_SAMTEC_TSM-104-01-X-DV]
LD6  LED, Green, 0603  [LED_0603_GREEN]
R97  330R  [R0402]
SB1  Solder: YES  [SOLDER-BRIDGE_R0603-0R]  (hidden comment: SB_ON)
U3  LD1117S50TR  [REG_SOT223-TAB]
U4  LD1117S33TR  [REG_SOT223-TAB]

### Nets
3V3: C7.2 JP2.1(COMMON) SB1.2
5V: C5.2 JP3.2 JP3.4 JP3.6 JP3.8 R97.1 U4.3(Vin)
5V_ARD: C4.2 JP3.3 U3.2(Vout) U3.4(Tab)
5V_ST_LINK: JP3.1
5V_USB_CHARGER: JP3.7
5V_USB_FS: JP3.5
GND: C3.1 C4.1 C5.1 C6.1 C7.1 JP1.1(COMMON) JP1.2(NO) LD6.2 U3.1(Gnd) U4.1(Gnd)
LDO_3V3: C6.2 SB1.1 U4.2(Vout) U4.4(Tab)
VDD_MCU: JP2.2(NO)
VIN: C3.2 U3.3(Vin)
NetLD6_1: LD6.1 R97.2

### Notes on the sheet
- 5V  PWR SELECTION FROM EXTERNAL SOURCES
- PWR TREE
- 5V_USB_ST_LINK
- USB_ST_LINK
- 5V
- SWITCH
- 5V_USB_FS
- 3V3
- USB_FS
- 5V_ARD
- BAT60
- LDO 5V/800mA
- ARD_VIN
- ARDUINO
- Connect only one jumper to supply the DISCO from one of the external 5V.
  If the DK board is connected to an external 220/5V USB Charger, used Jumper on pin 7/8.
- 3V3_ST_LINK
- 5V PWR FROM ARDUINO (VIN < 11.5V)
- JUMPER
- STM32F103 ST LINK
- LED ST LINK
- From Arduino power pin
- Output: 5V / Up to 800mA
- 5V_USB_CHARGER
- 5V_ST_LINK
- ST LINK DEBUG
- TAG
- VDD_MCU
- VDD
- VDDA
- MCU_STM32F413H
- 3V3 PWR
- LDO 3V3/800mA
- VREF+
- VBAT
- VDD_USB
- Output: 3V3 / Up to 800mA
- PSRAM
- QSPI
- (near JP2) IDD
- LDO 1V8/150mA
- 1V8
- Audio WM8994
- (near JP2) Jumper to measure IDD of the MCU
- VDD_MCU= supply of MCU Power pins
- Microphones
- LCD_FRIDA
- Open solder bridge if Discovery is supplied
  from +3V3 of extension connector
- LCD_BACKLIGHT
- CTP
- SD-CARD
- GND PROBE
- WIFI ISM43362-M3G-L44

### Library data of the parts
C3-C6 = Cap_10uF_X5R_10%_0805: Capacitor,10uF,25V,X5R,10%,0805,YAGEO; Manuf_Part_1: CC0805KRX5R8BB106; Fitted: YES; Ordered_By: Subcon
C7 = Cap_100nF_X7R_10%_0402: as C57 on sheet 06_Peripherals
HW14 HW15 = Shunt 2.54mm: SHUNT 2.54mm BLACK; Manuf_1: SAMTEC; Manuf_Part_1: SNT-100-BK-G; Fitted: YES; Ordered_By: Subcon
JP1 JP2 = TSW-102-07-x-S: Connector jumper 1 position; Manuf_1: SAMTEC; Manuf_Part_2: 4711955140470; Manuf_2: KONTEC; Order_Code: 423-2841; Fitted: YES; Ordered_By: Subcon
JP3 = Header_4X2_SMD: Header, 4-Pins, Double row Vertical, SMD, 2.54; Manuf_1: SAMTEC; Fitted: YES; Ordered_By: Subcon
LD6 = LED_green: as LD7 on sheet 05_USB_OTG_FS
R97 = Res_330_1%_0402: as R107 on sheet 05_USB_OTG_FS
SB1 = SB_ON: Solder Bridge ON; Ordered_by: Subcon
U3 = LD1117S50TR: IC REG LDO 5V 0.8A SOT223; Manuf_1: STM; ECCN_US/EU: EAR99/NEC; Ref St: 9176133; Fitted: YES
U4 = LD1117S33TR: LOW DROP FIXED AND ADJUSTABLE POSITIVE VOLTAGE REGULATORS (3.3 Volts); Manuf_1: STM; ECCN_US/EU: EAR99/NEC; Fitted: YES

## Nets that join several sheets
3V3: 00_MCU (6 pins), 01_PSRAM (6 pins), 02_QSPI (C28.2 R21.2 R31.2 U9.8), 04_LCD (12 pins), 03_Audio (26 pins), 05_USB_OTG_FS (R64.2 R66.2 R107.2 R108.1), 06_Peripherals (20 pins), 07_Arduino_ Connectors (CN7.2 CN7.4 R96.2), 09_Power (C7.2 JP2.1 SB1.2)
5V: 04_LCD (L6.1), 05_USB_OTG_FS (U15.5), 07_Arduino_ Connectors (CN7.5), 08_ST_LINK_V2-1 (D4.1), 09_Power (7 pins)
5V_ARD: 07_Arduino_ Connectors (R95.1), 08_ST_LINK_V2-1 (D1.1), 09_Power (C4.2 JP3.3 U3.2 U3.4)
5V_ST_LINK: 08_ST_LINK_V2-1 (C27.2 SB4.2 U10.6 U10.7), 09_Power (JP3.1)
5V_USB_CHARGER: 08_ST_LINK_V2-1 (11 pins), 09_Power (JP3.7)
5V_USB_FS: 05_USB_OTG_FS (R67.2), 08_ST_LINK_V2-1 (D3.1), 09_Power (JP3.5)
GND: Top (H1.1 H2.1 H3.1 H4.1), 00_MCU (37 pins), 01_PSRAM (7 pins), 02_QSPI (C28.1 R20.2 U9.4), 04_LCD (12 pins), 03_Audio (45 pins), 05_USB_OTG_FS (13 pins), 06_Peripherals (32 pins), 07_Arduino_ Connectors (6 pins), 08_ST_LINK_V2-1 (43 pins), 09_Power (10 pins)
VDD_MCU: 00_MCU (26 pins), 09_Power (JP2.2)
VIN: 07_Arduino_ Connectors (CN7.8), 09_Power (C3.2 U3.3)
VREF+: 00_MCU (C48.1 C51.2 R51.1 U13.32), 07_Arduino_ Connectors (C42.2 R40.2)
ARD_A0: 00_MCU (U13.26), 07_Arduino_ Connectors (CN9.1)
ARD_A1: 00_MCU (U13.35), 07_Arduino_ Connectors (CN9.2)
ARD_A2: 00_MCU (U13.36), 07_Arduino_ Connectors (CN9.3)
ARD_A3: 00_MCU (U13.41), 07_Arduino_ Connectors (CN9.4)
ARD_A4: 00_MCU (U13.47), 07_Arduino_ Connectors (SB19.1)
ARD_A5: 00_MCU (U13.44), 07_Arduino_ Connectors (SB21.1)
ARD_D0: 00_MCU (U13.18), 07_Arduino_ Connectors (CN8.1)
ARD_D1: 00_MCU (U13.19), 07_Arduino_ Connectors (CN8.2)
ARD_D2: 00_MCU (U13.128), 07_Arduino_ Connectors (CN8.3)
ARD_D3: 00_MCU (U13.22), 07_Arduino_ Connectors (CN8.4)
ARD_D4: 00_MCU (U13.136), 07_Arduino_ Connectors (CN8.5)
ARD_D5: 00_MCU (U13.5), 07_Arduino_ Connectors (CN8.6)
ARD_D6: 00_MCU (U13.46), 07_Arduino_ Connectors (CN8.7)
ARD_D7: 00_MCU (U13.7), 07_Arduino_ Connectors (CN8.8)
ARD_D8: 00_MCU (U13.40), 07_Arduino_ Connectors (CN6.1)
ARD_D9: 00_MCU (U13.139), 07_Arduino_ Connectors (CN6.2)
ARD_D10: 00_MCU (U13.110), 07_Arduino_ Connectors (CN6.3)
ARD_D11: 00_MCU (U13.135), 07_Arduino_ Connectors (CN6.4)
ARD_D12: 00_MCU (U13.134), 07_Arduino_ Connectors (CN6.5)
ARD_D13: 00_MCU (U13.73), 07_Arduino_ Connectors (CN6.6 SB5.1)
ARD_D14: 00_MCU (R102.1 U13.70), 07_Arduino_ Connectors (CN6.9 SB20.1)
ARD_D15: 00_MCU (R104.1 U13.69), 07_Arduino_ Connectors (CN6.10 SB24.1)
B_USER: 00_MCU (U13.34), 06_Peripherals (SB6.1)
CODEC_CK: 00_MCU (U13.117), 03_Audio (R23.1 TP14.1)
CODEC_ext_SD: 00_MCU (U13.28), 03_Audio (R22.1 TP5.1)
CODEC_INT: 00_MCU (U13.132), 03_Audio (R29.1 TP8.1)
CODEC_MCK: 00_MCU (U13.37), 03_Audio (R26.2 TP10.1)
CODEC_SD: 00_MCU (U13.29), 03_Audio (R33.1 TP7.1)
CODEC_WS: 00_MCU (U13.140), 03_Audio (R28.1 TP11.1)
CTP_INT: 00_MCU (U13.27), 04_LCD (CN10.2)
DFSDM1_CKOUT: 00_MCU (U13.100), 03_Audio (TP2.1 U8.14)
DFSDM1_DATIN1: 00_MCU (U13.122), 03_Audio (TP13.1 U8.2)
DFSDM2_CKOUT: 00_MCU (U13.116), 03_Audio (TP15.1 U8.6)
DFSDM2_DATIN1: 00_MCU (U13.43), 03_Audio (TP12.1 U8.10)
DFSDM2_DATIN7: 00_MCU (U13.137), 03_Audio (CN12.7 TP9.1)
I2CFMP1_SCL: 00_MCU (R56.1 U13.96), 04_LCD (CN10.5), 03_Audio (TP1.1 U11.H1)
I2CFMP1_SDA: 00_MCU (R57.1 U13.97), 04_LCD (CN10.4), 03_Audio (TP16.1 U11.F3)
LCD-CTP_RST: 00_MCU (U13.74), 04_LCD (5 pins)
LCD-PSRAM_D0: 00_MCU (U13.85), 01_PSRAM (U14.B6), 04_LCD (CN15.7 CN16.18)
LCD-PSRAM_D1: 00_MCU (U13.86), 01_PSRAM (U14.C5), 04_LCD (CN15.8 CN16.17)
LCD-PSRAM_D2: 00_MCU (U13.114), 01_PSRAM (U14.C6), 04_LCD (CN15.9 CN16.16)
LCD-PSRAM_D3: 00_MCU (U13.115), 01_PSRAM (U14.D5), 04_LCD (CN15.11 CN16.15)
LCD-PSRAM_D4: 00_MCU (U13.58), 01_PSRAM (U14.E5), 04_LCD (CN15.15 CN16.14)
LCD-PSRAM_D5: 00_MCU (U13.59), 01_PSRAM (U14.F5), 04_LCD (CN15.16 CN16.13)
LCD-PSRAM_D6: 00_MCU (U13.60), 01_PSRAM (U14.F6), 04_LCD (CN15.17 CN16.12)
LCD-PSRAM_D7: 00_MCU (U13.63), 01_PSRAM (U14.G6), 04_LCD (CN15.18 CN16.11)
LCD-PSRAM_D8: 00_MCU (U13.64), 01_PSRAM (U14.B1), 04_LCD (CN15.19 CN16.10)
LCD-PSRAM_D9: 00_MCU (U13.65), 01_PSRAM (U14.C1), 04_LCD (CN15.20 CN16.9)
LCD-PSRAM_D10: 00_MCU (U13.66), 01_PSRAM (U14.C2), 04_LCD (CN15.21 CN16.8)
LCD-PSRAM_D11: 00_MCU (U13.67), 01_PSRAM (U14.D2), 04_LCD (CN15.22 CN16.7)
LCD-PSRAM_D12: 00_MCU (U13.68), 01_PSRAM (U14.E2), 04_LCD (CN15.23 CN16.6)
LCD-PSRAM_D13: 00_MCU (U13.77), 01_PSRAM (U14.F2), 04_LCD (CN15.24 CN16.5)
LCD-PSRAM_D14: 00_MCU (U13.78), 01_PSRAM (U14.F1), 04_LCD (CN15.25 CN16.4)
LCD-PSRAM_D15: 00_MCU (U13.79), 01_PSRAM (U14.G1), 04_LCD (CN15.26 CN16.3)
LCD-PSRAM_NOE: 00_MCU (U13.118), 01_PSRAM (U14.A2), 04_LCD (CN15.6 CN16.19)
LCD-PSRAM_NWE: 00_MCU (U13.119), 01_PSRAM (R61.1), 04_LCD (CN15.3 CN16.20)
LCD-RS_A0: 00_MCU (R46.2), 04_LCD (CN15.1 CN16.21)
LCD_BL_CTRL: 00_MCU (U13.4), 04_LCD (CN15.2 L2.1)
LCD_NE3: 00_MCU (U13.125), 04_LCD (CN15.5 CN16.22 R105.2)
LCD_TE: 00_MCU (U13.75), 04_LCD (CN15.13 CN16.2)
LED1_RED: 00_MCU (U13.2), 06_Peripherals (R94.2)
LED2_GREEN: 00_MCU (U13.45), 06_Peripherals (R93.1)
MEMS_LED: 00_MCU (U13.3), 03_Audio (CN12.12)
NRST: 00_MCU (U13.25), 06_Peripherals (SB7.1 SB10.1), 07_Arduino_ Connectors (CN7.3), 08_ST_LINK_V2-1 (R90.2 SB16.2)
PSRAM_A0: 00_MCU (R46.1 U13.10), 01_PSRAM (U14.A3)
PSRAM_A1: 00_MCU (U13.11), 01_PSRAM (U14.A4)
PSRAM_A2: 00_MCU (U13.12), 01_PSRAM (U14.A5)
PSRAM_A3: 00_MCU (U13.13), 01_PSRAM (U14.B3)
PSRAM_A4: 00_MCU (U13.14), 01_PSRAM (U14.B4)
PSRAM_A5: 00_MCU (U13.15), 01_PSRAM (U14.C3)
PSRAM_A6: 00_MCU (U13.50), 01_PSRAM (U14.C4)
PSRAM_A7: 00_MCU (U13.53), 01_PSRAM (U14.D4)
PSRAM_A8: 00_MCU (U13.54), 01_PSRAM (U14.H2)
PSRAM_A9: 00_MCU (U13.55), 01_PSRAM (U14.H3)
PSRAM_A10: 00_MCU (U13.56), 01_PSRAM (U14.H4)
PSRAM_A11: 00_MCU (U13.57), 01_PSRAM (U14.H5)
PSRAM_A12: 00_MCU (U13.87), 01_PSRAM (U14.G3)
PSRAM_A13: 00_MCU (U13.88), 01_PSRAM (U14.G4)
PSRAM_A14: 00_MCU (U13.89), 01_PSRAM (U14.F3)
PSRAM_A15: 00_MCU (U13.90), 01_PSRAM (U14.F4)
PSRAM_A16: 00_MCU (U13.80), 01_PSRAM (U14.E4)
PSRAM_A17: 00_MCU (U13.81), 01_PSRAM (U14.D3)
PSRAM_NBL0: 00_MCU (U13.141), 01_PSRAM (U14.A1)
PSRAM_NBL1: 00_MCU (U13.142), 01_PSRAM (U14.B2)
PSRAM_NE1: 00_MCU (U13.123), 01_PSRAM (R59.1)
QSPI_BK1_IO0: 00_MCU (U13.20), 02_QSPI (TP3.1 U9.5)
QSPI_BK1_IO1: 00_MCU (U13.21), 02_QSPI (TP6.1 U9.2)
QSPI_BK1_IO2: 00_MCU (U13.1), 02_QSPI (U9.3)
QSPI_BK1_IO3: 00_MCU (U13.82), 02_QSPI (U9.7)
QSPI_BK1_NCS: 00_MCU (U13.91), 02_QSPI (R31.1 U9.1)
QSPI_CLK: 00_MCU (U13.48), 02_QSPI (R20.1 R21.1 TP4.1 U9.6)
SD_CLK: 00_MCU (U13.113), 06_Peripherals (CN1.5)
SD_CMD: 00_MCU (U13.42), 06_Peripherals (CN1.3 R83.1)
SD_D0: 00_MCU (U13.98), 06_Peripherals (CN1.7 R84.1)
SD_D1: 00_MCU (U13.99), 06_Peripherals (CN1.8 R85.1)
SD_D2: 00_MCU (U13.111), 06_Peripherals (CN1.1 R81.1)
SD_D3: 00_MCU (U13.112), 06_Peripherals (CN1.2 R82.1)
SD_Detect: 00_MCU (U13.49), 06_Peripherals (R79.1)
STLINK_JTCK_SWCLK: 00_MCU (U13.109), 08_ST_LINK_V2-1 (R92.2 SB18.2)
STLINK_JTDO-SWO: 00_MCU (U13.133), 08_ST_LINK_V2-1 (R91.2 SB17.2)
STLINK_JTMS_SWDIO: 00_MCU (U13.105), 08_ST_LINK_V2-1 (R89.2 SB15.2)
STLK_MCO: 00_MCU (R50.2), 08_ST_LINK_V2-1 (C8.2 R7.2)
USB_OTG_FS_ID: 00_MCU (U13.102), 05_USB_OTG_FS (CN17.4 U20.1)
USB_OTG_FS_N: 00_MCU (U13.103), 05_USB_OTG_FS (U19.1)
USB_OTG_FS_OVRCR: 00_MCU (U13.92), 05_USB_OTG_FS (R65.1)
USB_OTG_FS_P: 00_MCU (U13.104), 05_USB_OTG_FS (U19.3)
USB_OTG_FS_PWR_EN: 00_MCU (U13.93), 05_USB_OTG_FS (R63.1)
USB_OTG_FS_VBUS: 00_MCU (U13.101), 05_USB_OTG_FS (6 pins)
VCP_RX: 00_MCU (U13.124), 08_ST_LINK_V2-1 (R19.1)
VCP_TX: 00_MCU (U13.129), 08_ST_LINK_V2-1 (R15.1)
WIFI_DRDY: 00_MCU (U13.127), 06_Peripherals (SB9.1 SB12.1)
WIFI_RST: 00_MCU (R49.2), 06_Peripherals (M1.34 R74.1 SB10.2)
WIFI_SPI_CSN: 00_MCU (U13.126), 06_Peripherals (R68.2 SB8.1 SB11.1)
WIFI_WKUP: 00_MCU (U13.76), 06_Peripherals (M1.16 R71.1)

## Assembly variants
F413ZHT6: not fitted C8 C42 C43 C44 CN3 CN4 CN11 CN13 CN14 CN15 HW18 L8 R11 R17 R18 R20 R21 R25 R44 R45 R53 R54 R72 R76 R77 R78 R88 R99 SB3 SB4 SB10 SB11 SB12 SB13 SB20 SB23 SB24 TP1 TP2 TP3 TP4 TP5 TP6 TP7 TP8 TP9 TP10 TP11 TP12 TP13 TP14 TP15 TP16 TP17 TP18 TP19 TP20 TP21 TP22 U1 U2 X2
